One B-rep face of a CAD part: STEP entity #63150.
In plain terms, the planar face has unit normal (0, 0, 1).
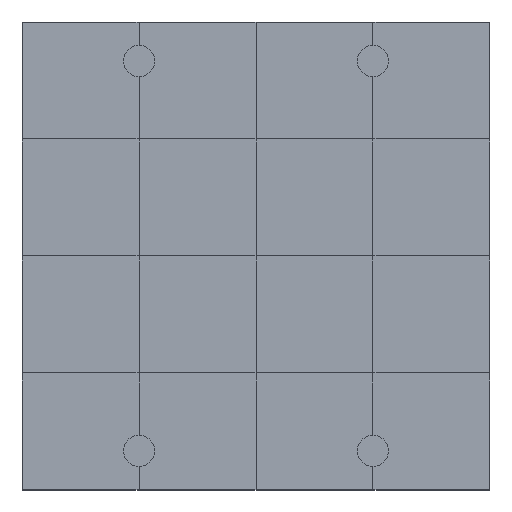
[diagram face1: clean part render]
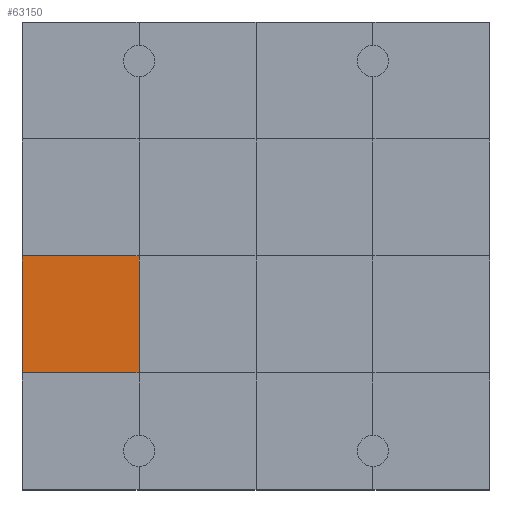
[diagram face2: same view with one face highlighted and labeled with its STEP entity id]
Its self-contained STEP definition (entity closure, numbers rounded to 3 decimals):
#62700 = VERTEX_POINT('',#62701);
#62701 = CARTESIAN_POINT('',(0.,3.,1.2));
#62715 = PLANE('',#62716);
#62716 = AXIS2_PLACEMENT_3D('',#62717,#62718,#62719);
#62717 = CARTESIAN_POINT('',(0.,3.,0.));
#62718 = DIRECTION('',(1.,0.,-0.));
#62719 = DIRECTION('',(0.,0.,1.));
#62741 = PLANE('',#62742);
#62742 = AXIS2_PLACEMENT_3D('',#62743,#62744,#62745);
#62743 = CARTESIAN_POINT('',(0.,0.,1.2));
#62744 = DIRECTION('',(0.,0.,1.));
#62745 = DIRECTION('',(1.,0.,-0.));
#62892 = VERTEX_POINT('',#62893);
#62893 = CARTESIAN_POINT('',(3.,3.,1.2));
#62914 = EDGE_CURVE('',#62700,#62892,#62915,.T.);
#62915 = SURFACE_CURVE('',#62916,(#62920,#62927),.PCURVE_S1.);
#62916 = LINE('',#62917,#62918);
#62917 = CARTESIAN_POINT('',(0.,3.,1.2));
#62918 = VECTOR('',#62919,1.);
#62919 = DIRECTION('',(1.,0.,-0.));
#62920 = PCURVE('',#62741,#62921);
#62921 = DEFINITIONAL_REPRESENTATION('',(#62922),#62926);
#62922 = LINE('',#62923,#62924);
#62923 = CARTESIAN_POINT('',(0.,3.));
#62924 = VECTOR('',#62925,1.);
#62925 = DIRECTION('',(1.,0.));
#62926 = ( GEOMETRIC_REPRESENTATION_CONTEXT(2) 
PARAMETRIC_REPRESENTATION_CONTEXT() REPRESENTATION_CONTEXT('2D SPACE',''
  ) );
#62927 = PCURVE('',#62928,#62933);
#62928 = PLANE('',#62929);
#62929 = AXIS2_PLACEMENT_3D('',#62930,#62931,#62932);
#62930 = CARTESIAN_POINT('',(0.,3.,1.2));
#62931 = DIRECTION('',(0.,0.,1.));
#62932 = DIRECTION('',(1.,0.,-0.));
#62933 = DEFINITIONAL_REPRESENTATION('',(#62934),#62938);
#62934 = LINE('',#62935,#62936);
#62935 = CARTESIAN_POINT('',(0.,0.));
#62936 = VECTOR('',#62937,1.);
#62937 = DIRECTION('',(1.,0.));
#62938 = ( GEOMETRIC_REPRESENTATION_CONTEXT(2) 
PARAMETRIC_REPRESENTATION_CONTEXT() REPRESENTATION_CONTEXT('2D SPACE',''
  ) );
#62973 = VERTEX_POINT('',#62974);
#62974 = CARTESIAN_POINT('',(0.,6.,1.2));
#63000 = EDGE_CURVE('',#62700,#62973,#63001,.T.);
#63001 = SURFACE_CURVE('',#63002,(#63006,#63013),.PCURVE_S1.);
#63002 = LINE('',#63003,#63004);
#63003 = CARTESIAN_POINT('',(0.,3.,1.2));
#63004 = VECTOR('',#63005,1.);
#63005 = DIRECTION('',(-0.,1.,0.));
#63006 = PCURVE('',#62715,#63007);
#63007 = DEFINITIONAL_REPRESENTATION('',(#63008),#63012);
#63008 = LINE('',#63009,#63010);
#63009 = CARTESIAN_POINT('',(1.2,0.));
#63010 = VECTOR('',#63011,1.);
#63011 = DIRECTION('',(0.,-1.));
#63012 = ( GEOMETRIC_REPRESENTATION_CONTEXT(2) 
PARAMETRIC_REPRESENTATION_CONTEXT() REPRESENTATION_CONTEXT('2D SPACE',''
  ) );
#63013 = PCURVE('',#62928,#63014);
#63014 = DEFINITIONAL_REPRESENTATION('',(#63015),#63019);
#63015 = LINE('',#63016,#63017);
#63016 = CARTESIAN_POINT('',(0.,0.));
#63017 = VECTOR('',#63018,1.);
#63018 = DIRECTION('',(0.,1.));
#63019 = ( GEOMETRIC_REPRESENTATION_CONTEXT(2) 
PARAMETRIC_REPRESENTATION_CONTEXT() REPRESENTATION_CONTEXT('2D SPACE',''
  ) );
#63150 = ADVANCED_FACE('',(#63151),#62928,.T.);
#63151 = FACE_BOUND('',#63152,.T.);
#63152 = EDGE_LOOP('',(#63153,#63154,#63155,#63183));
#63153 = ORIENTED_EDGE('',*,*,#63000,.F.);
#63154 = ORIENTED_EDGE('',*,*,#62914,.T.);
#63155 = ORIENTED_EDGE('',*,*,#63156,.T.);
#63156 = EDGE_CURVE('',#62892,#63157,#63159,.T.);
#63157 = VERTEX_POINT('',#63158);
#63158 = CARTESIAN_POINT('',(3.,6.,1.2));
#63159 = SURFACE_CURVE('',#63160,(#63164,#63171),.PCURVE_S1.);
#63160 = LINE('',#63161,#63162);
#63161 = CARTESIAN_POINT('',(3.,3.,1.2));
#63162 = VECTOR('',#63163,1.);
#63163 = DIRECTION('',(-0.,1.,0.));
#63164 = PCURVE('',#62928,#63165);
#63165 = DEFINITIONAL_REPRESENTATION('',(#63166),#63170);
#63166 = LINE('',#63167,#63168);
#63167 = CARTESIAN_POINT('',(3.,0.));
#63168 = VECTOR('',#63169,1.);
#63169 = DIRECTION('',(0.,1.));
#63170 = ( GEOMETRIC_REPRESENTATION_CONTEXT(2) 
PARAMETRIC_REPRESENTATION_CONTEXT() REPRESENTATION_CONTEXT('2D SPACE',''
  ) );
#63171 = PCURVE('',#63172,#63177);
#63172 = PLANE('',#63173);
#63173 = AXIS2_PLACEMENT_3D('',#63174,#63175,#63176);
#63174 = CARTESIAN_POINT('',(3.,3.,1.2));
#63175 = DIRECTION('',(0.,0.,1.));
#63176 = DIRECTION('',(1.,0.,-0.));
#63177 = DEFINITIONAL_REPRESENTATION('',(#63178),#63182);
#63178 = LINE('',#63179,#63180);
#63179 = CARTESIAN_POINT('',(0.,0.));
#63180 = VECTOR('',#63181,1.);
#63181 = DIRECTION('',(0.,1.));
#63182 = ( GEOMETRIC_REPRESENTATION_CONTEXT(2) 
PARAMETRIC_REPRESENTATION_CONTEXT() REPRESENTATION_CONTEXT('2D SPACE',''
  ) );
#63183 = ORIENTED_EDGE('',*,*,#63184,.F.);
#63184 = EDGE_CURVE('',#62973,#63157,#63185,.T.);
#63185 = SURFACE_CURVE('',#63186,(#63190,#63197),.PCURVE_S1.);
#63186 = LINE('',#63187,#63188);
#63187 = CARTESIAN_POINT('',(0.,6.,1.2));
#63188 = VECTOR('',#63189,1.);
#63189 = DIRECTION('',(1.,0.,-0.));
#63190 = PCURVE('',#62928,#63191);
#63191 = DEFINITIONAL_REPRESENTATION('',(#63192),#63196);
#63192 = LINE('',#63193,#63194);
#63193 = CARTESIAN_POINT('',(0.,3.));
#63194 = VECTOR('',#63195,1.);
#63195 = DIRECTION('',(1.,0.));
#63196 = ( GEOMETRIC_REPRESENTATION_CONTEXT(2) 
PARAMETRIC_REPRESENTATION_CONTEXT() REPRESENTATION_CONTEXT('2D SPACE',''
  ) );
#63197 = PCURVE('',#63198,#63203);
#63198 = PLANE('',#63199);
#63199 = AXIS2_PLACEMENT_3D('',#63200,#63201,#63202);
#63200 = CARTESIAN_POINT('',(0.,6.,1.2));
#63201 = DIRECTION('',(0.,0.,1.));
#63202 = DIRECTION('',(1.,0.,-0.));
#63203 = DEFINITIONAL_REPRESENTATION('',(#63204),#63208);
#63204 = LINE('',#63205,#63206);
#63205 = CARTESIAN_POINT('',(0.,0.));
#63206 = VECTOR('',#63207,1.);
#63207 = DIRECTION('',(1.,0.));
#63208 = ( GEOMETRIC_REPRESENTATION_CONTEXT(2) 
PARAMETRIC_REPRESENTATION_CONTEXT() REPRESENTATION_CONTEXT('2D SPACE',''
  ) );
